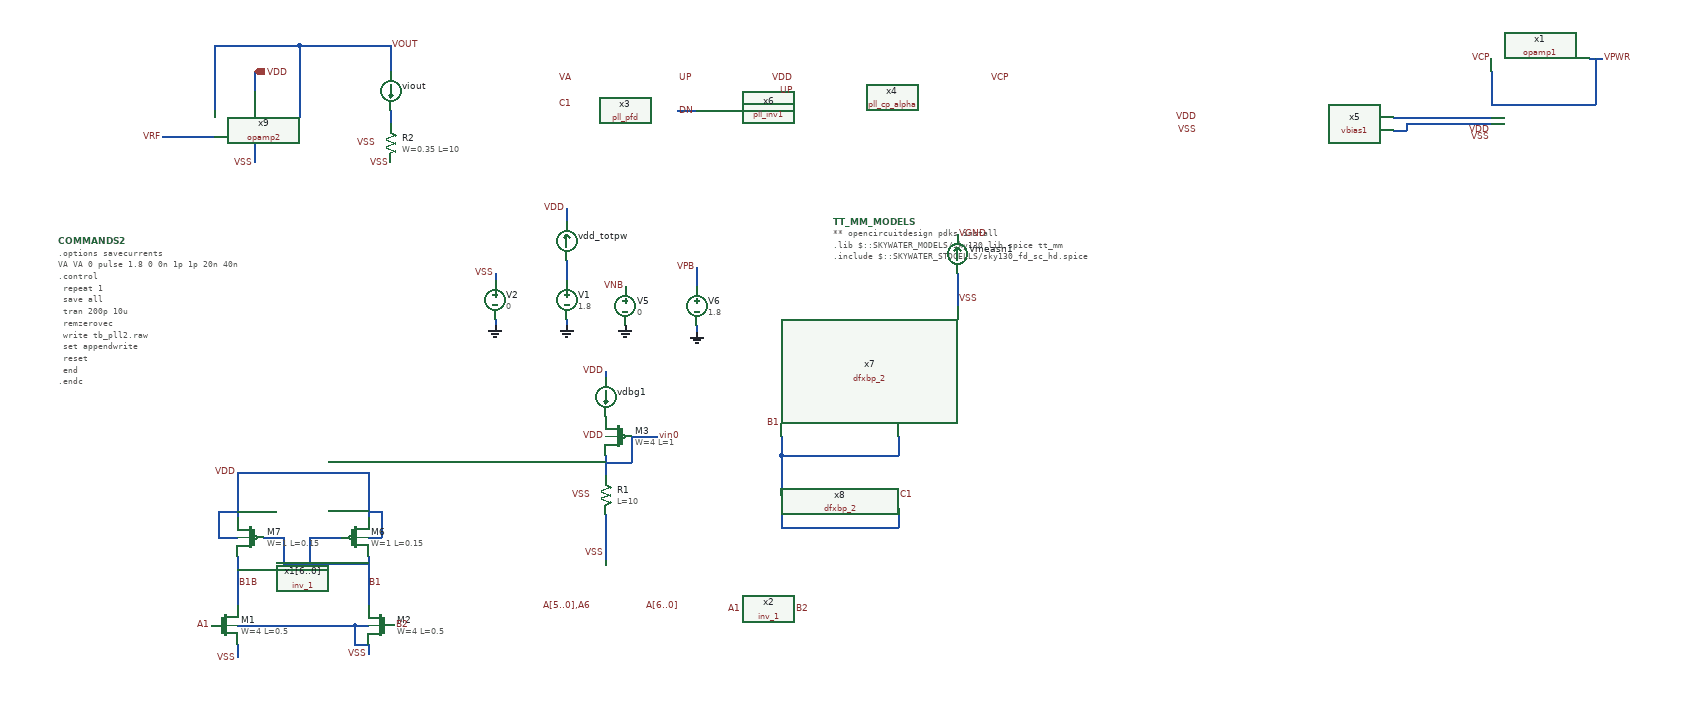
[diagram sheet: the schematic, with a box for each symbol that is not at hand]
v {xschem version=3.4.4 file_version=1.2
}
G {}
K {}
V {}
S {}
E {}
B 2 730 -870 1530 -470 {flags=graph
y1=-0.041
y2=3.9
ypos1=0
ypos2=2
divy=5
subdivy=1
unity=1
x1=8.63019e-06
x2=8.82941e-06
divx=5
subdivx=1
xlabmag=1.0
ylabmag=1.0


dataset=-1
unitx=1
logx=0
logy=0



color="4 5 8 10 10"
node="A1
\\"2 B1 +\\"
\\"2 B1B +\\"
B2
B3"
hilight_wave=0}
B 2 2330 -1270 3130 -870 {flags=graph
y1=-0.013
y2=3.9
ypos1=0
ypos2=2
divy=5
subdivy=1
unity=1
x1=8.63019e-06
x2=8.82941e-06
divx=5
subdivx=1
xlabmag=1.0
ylabmag=1.0


dataset=-1
unitx=1
logx=0
logy=0






color="4 5"
node="\\"UP 2 +\\"
DN"}
B 2 2330 -1670 3130 -1270 {flags=graph
y1=-0.00053
y2=5.9
ypos1=0
ypos2=2
divy=5
subdivy=1
unity=1
x1=8.63019e-06
x2=8.82941e-06
divx=5
subdivx=1
xlabmag=1.0
ylabmag=1.0


dataset=-1
unitx=1
logx=0
logy=0








rainbow=0
color="5 8 7"
node="\\"VA 4 +\\"
\\"C1 2 +\\"
\\"B1\\""}
B 2 1530 -870 2330 -470 {flags=graph
y1=-0.003
y2=0.0032
ypos1=0
ypos2=2
divy=5
subdivy=1
unity=1
x1=8.63019e-06
x2=8.82941e-06
divx=5
subdivx=1
xlabmag=1.0
ylabmag=1.0


dataset=-1
unitx=1
logx=0
logy=0







color=4
node=i(vdd_totpw)}
B 2 2330 -870 3130 -470 {flags=graph
y1=-1.9e-07
y2=1.1
ypos1=0
ypos2=2
divy=5
subdivy=1
unity=1
x1=8.63019e-06
x2=8.82941e-06
divx=5
subdivx=1
xlabmag=1.0
ylabmag=1.0


dataset=-1
unitx=1
logx=0
logy=0






color="18 8"
node="VPWR
VCP"}
N 1740 -1480 1740 -1470 {
lab=VPB}
N 1740 -1410 1740 -1400 {
lab=GND}
N 1740 -1500 1740 -1480 {
lab=VPB}
N 1430 -1490 1430 -1480 {
lab=VSS}
N 1540 -1490 1540 -1480 {
lab=#net1}
N 1430 -1420 1430 -1410 {
lab=GND}
N 1540 -1420 1540 -1410 {
lab=GND}
N 1600 -1340 1600 -1330 {
lab=VDD}
N 1600 -1060 1600 -1050 {
lab=VSS}
N 1600 -1120 1600 -1060 {
lab=VSS}
N 1540 -1590 1540 -1570 {
lab=VDD}
N 1540 -1510 1540 -1490 {
lab=#net1}
N 1600 -1210 1600 -1180 {
lab=vin0}
N 2140 -1490 2140 -1440 {
lab=VSS}
N 1640 -1240 1680 -1240 {
lab=vin0}
N 1640 -1240 1640 -1200 {
lab=vin0}
N 1600 -1200 1640 -1200 {
lab=vin0}
N 3110 -1820 3130 -1820 {
lab=VPWR}
N 2810 -1730 2960 -1730 {
lab=#net2}
N 2830 -1720 2960 -1720 {
lab=#net3}
N 2830 -1720 2830 -1710 {
lab=#net3}
N 2810 -1710 2830 -1710 {
lab=#net3}
N 3120 -1820 3120 -1750 {
lab=VPWR}
N 2960 -1750 3120 -1750 {
lab=VPWR}
N 2960 -1800 2960 -1750 {
lab=VPWR}
N 1710 -1740 1740 -1740 {
lab=DN}
N 1810 -1740 1870 -1750 {
lab=#net4}
N 1870 -1750 1890 -1750 {
lab=#net4}
N 2050 -1240 2050 -1210 {
lab=#net5}
N 1870 -1210 2050 -1210 {
lab=#net5}
N 1870 -1240 1870 -1210 {
lab=#net5}
N 2050 -1130 2050 -1100 {
lab=#net6}
N 1870 -1100 2050 -1100 {
lab=#net6}
N 1870 -1130 1870 -1100 {
lab=#net6}
N 1870 -1210 1870 -1150 {
lab=#net5}
N 1145 -1085 1145 -1035 {
lab=B1B}
N 1165 -1085 1195 -1085 {
lab=B1B}
N 1075 -1085 1105 -1085 {
lab=B1}
N 1105 -1085 1105 -1045 {
lab=B1}
N 1105 -1045 1235 -1045 {
lab=B1}
N 1145 -1085 1165 -1085 {
lab=B1B}
N 1035 -1035 1145 -1035 {
lab=B1B}
N 1235 -1185 1235 -1115 {
lab=VDD}
N 1035 -1185 1035 -1115 {
lab=VDD}
N 1005 -1085 1035 -1085 {
lab=VDD}
N 1005 -1125 1005 -1085 {
lab=VDD}
N 1005 -1125 1035 -1125 {
lab=VDD}
N 1235 -1085 1255 -1085 {
lab=VDD}
N 1255 -1125 1255 -1085 {
lab=VDD}
N 1235 -1125 1255 -1125 {
lab=VDD}
N 1235 -1055 1235 -980 {
lab=B1}
N 1035 -1185 1235 -1185 {
lab=VDD}
N 1235 -920 1235 -905 {
lab=VSS}
N 1215 -920 1235 -920 {
lab=VSS}
N 1215 -950 1215 -920 {
lab=VSS}
N 1215 -950 1235 -950 {
lab=VSS}
N 1035 -920 1035 -900 {
lab=VSS}
N 1035 -950 1215 -950 {
lab=VSS}
N 1035 -1055 1035 -980 {
lab=B1B}
N 1270 -1840 1270 -1800 {
lab=VOUT}
N 1060 -1800 1060 -1770 {
lab=VDD}
N 1060 -1690 1060 -1660 {
lab=VSS}
N 1130 -1840 1130 -1730 {
lab=VOUT}
N 1000 -1840 1130 -1840 {
lab=VOUT}
N 1000 -1840 1000 -1740 {
lab=VOUT}
N 920 -1700 1000 -1700 {
lab=VRF}
N 1130 -1840 1270 -1840 {
lab=VOUT}
N 1270 -1740 1270 -1720 {
lab=#net7}
C {devices/code.sym} 1950 -1570 0 0 {name=TT_MM_MODELS
only_toplevel=true
format="tcleval( @value )"
value="
** opencircuitdesign pdks install
.lib $::SKYWATER_MODELS/sky130.lib.spice tt_mm
.include $::SKYWATER_STDCELLS/sky130_fd_sc_hd.spice                                                              
                        
"
spice_ignore=false}
C {devices/launcher.sym} 2200 -1410 0 0 {name=h17 
descr="Load waves" 
tclcommand="
xschem raw_read $netlist_dir/[file tail [file rootname [xschem get current_name]]].raw tran

"
}
C {devices/simulator_commands_shown.sym} 760 -1540 0 0 {name=COMMANDS2
simulator=ngspice
only_toplevel=false 
value="
.options savecurrents 
VA VA 0 pulse 1.8 0 0n 1p 1p 20n 40n
.control
  repeat 1
    save all
    tran 200p 10u
    remzerovec
    write tb_pll2.raw
    set appendwrite
    reset
    end
.endc
"}
C {devices/vsource.sym} 1630 -1440 0 0 {name=V5 value=0 savecurrent=false}
C {devices/gnd.sym} 1630 -1410 0 0 {name=l5 lab=GND}
C {devices/lab_pin.sym} 1630 -1470 2 1 {name=p6 sig_type=std_logic lab=VNB

}
C {devices/vsource.sym} 1740 -1440 0 0 {name=V6 value=1.8 savecurrent=false}
C {devices/gnd.sym} 1740 -1400 0 0 {name=l6 lab=GND}
C {devices/lab_pin.sym} 1740 -1500 2 1 {name=p14 sig_type=std_logic lab=VPB

}
C {devices/vsource.sym} 1540 -1450 0 0 {name=V1 value=1.8 savecurrent=false}
C {devices/gnd.sym} 1540 -1410 0 0 {name=l2 lab=GND}
C {devices/lab_pin.sym} 1540 -1590 2 1 {name=p19 sig_type=std_logic lab=VDD
}
C {devices/vsource.sym} 1430 -1450 0 0 {name=V2 value=0 savecurrent=false}
C {devices/gnd.sym} 1430 -1410 0 0 {name=l3 lab=GND}
C {devices/lab_pin.sym} 1430 -1490 2 1 {name=p28 sig_type=std_logic lab=VSS
}
C {devices/lab_pin.sym} 1600 -1340 2 1 {name=p2 sig_type=std_logic lab=VDD
}
C {sky130_fd_pr/pfet_01v8_lvt.sym} 1620 -1240 0 1 {name=M3
W=4
L=1
nf=1
mult=1
ad="'int((nf+1)/2) * W/nf * 0.29'" 
pd="'2*int((nf+1)/2) * (W/nf + 0.29)'"
as="'int((nf+2)/2) * W/nf * 0.29'" 
ps="'2*int((nf+2)/2) * (W/nf + 0.29)'"
nrd="'0.29 / W'" nrs="'0.29 / W'"
sa=0 sb=0 sd=0
model=pfet_01v8_lvt
spiceprefix=X
}
C {devices/lab_pin.sym} 1680 -1240 2 0 {name=p5 sig_type=std_logic lab=vin0
}
C {sky130_fd_pr/res_high_po_0p35.sym} 1600 -1150 0 0 {name=R1
L=10
model=res_high_po_0p35
spiceprefix=X
mult=1}
C {devices/ammeter.sym} 1600 -1300 0 0 {name=vdbg1 savecurrent=true}
C {devices/lab_pin.sym} 1580 -1150 2 1 {name=p43 sig_type=std_logic lab=VSS
}
C {devices/lab_pin.sym} 1600 -1240 2 1 {name=p44 sig_type=std_logic lab=VDD
}
C {devices/ammeter.sym} 1540 -1540 2 1 {name=vdd_totpw savecurrent=true}
C {devices/lab_pin.sym} 1600 -1060 2 1 {name=p3 sig_type=std_logic lab=VSS
}
C {sky130_stdcells/inv_1.sym} 1620 -980 0 0 {name=x1[6..0] VGND=VGND VNB=VGND VPB=VDD VPWR=VPWR prefix=sky130_fd_sc_hd__ }
C {devices/lab_pin.sym} 1660 -980 0 1 {name=p7 sig_type=std_logic lab=A[6..0]}
C {devices/lab_pin.sym} 1580 -980 0 0 {name=p9 sig_type=std_logic lab=A[5..0],A6}
C {devices/ammeter.sym} 2140 -1520 2 1 {name=Vmeasn1 savecurrent=true}
C {devices/lab_pin.sym} 2140 -1550 2 0 {name=p12 sig_type=std_logic lab=VGND
}
C {devices/lab_pin.sym} 2140 -1450 2 0 {name=p26 sig_type=std_logic lab=VSS
}
C {sky130_stdcells/inv_1.sym} 1850 -975 0 0 {name=x2 VGND=VGND VNB=VGND VPB=VDD VPWR=VPWR prefix=sky130_fd_sc_hd__ }
C {devices/lab_pin.sym} 1810 -975 2 1 {name=p29 sig_type=std_logic lab=A1
}
C {devices/lab_pin.sym} 1890 -975 0 1 {name=p30 sig_type=std_logic lab=B2
}
C {pll_pfd.sym} 1630 -1740 0 0 {name=x3 VSS=VSS VNB=VSS VPB=VDD VDD=VDD}
C {devices/lab_pin.sym} 1550 -1790 2 1 {name=p25 sig_type=std_logic lab=VA
}
C {devices/lab_pin.sym} 1890 -1790 0 0 {name=p32 sig_type=std_logic lab=VDD}
C {devices/lab_pin.sym} 1890 -1730 0 0 {name=p33 sig_type=std_logic lab=VSS}
C {devices/lab_pin.sym} 1710 -1740 0 1 {name=p11 sig_type=std_logic lab=DN}
C {devices/lab_pin.sym} 1710 -1790 0 1 {name=p8 sig_type=std_logic lab=UP}
C {devices/lab_pin.sym} 1550 -1750 0 0 {name=p31 sig_type=std_logic lab=C1
}
C {devices/lab_pin.sym} 3130 -1820 2 0 {name=p10 sig_type=std_logic lab=VPWR
}
C {opamp1.sym} 3030 -1810 0 0 {name=x1}
C {vbias1.sym} 2660 -1720 0 0 {name=x5}
C {devices/lab_pin.sym} 2510 -1730 0 0 {name=p4 sig_type=std_logic lab=VDD}
C {devices/lab_pin.sym} 2510 -1710 0 0 {name=p13 sig_type=std_logic lab=VSS}
C {devices/lab_pin.sym} 2960 -1710 0 0 {name=p15 sig_type=std_logic lab=VDD}
C {devices/lab_pin.sym} 2960 -1700 0 0 {name=p16 sig_type=std_logic lab=VSS}
C {devices/lab_pin.sym} 2190 -1790 2 0 {name=p17 sig_type=std_logic lab=VCP
}
C {devices/lab_pin.sym} 2960 -1820 2 1 {name=p18 sig_type=std_logic lab=VCP
}
C {pll_cp_alpha.sym} 2040 -1760 0 0 {name=x4}
C {pll_inv1.sym} 1790 -1740 0 0 {name=x6 VSS=VSS VNB=VNB VPB=VPB VDD=VDD}
C {devices/lab_pin.sym} 1890 -1770 0 0 {name=p1 sig_type=std_logic lab=UP}
C {sky130_stdcells/dfxbp_2.sym} 1960 -1250 0 0 {name=x7 VGND=VGND VNB=VNB VPB=VPB VPWR=VPWR prefix=sky130_fd_sc_hd__ }
C {devices/lab_pin.sym} 1870 -1260 0 0 {name=p20 sig_type=std_logic lab=B1
}
C {sky130_stdcells/dfxbp_2.sym} 1960 -1140 0 0 {name=x8 VGND=VGND VNB=VNB VPB=VPB VPWR=VPWR prefix=sky130_fd_sc_hd__ }
C {devices/lab_pin.sym} 2050 -1150 0 1 {name=p23 sig_type=std_logic lab=C1
}
C {sky130_fd_pr/pfet_01v8.sym} 1215 -1085 0 0 {name=M6
L=0.15
W=1
nf=1
mult=1
ad="'int((nf+1)/2) * W/nf * 0.29'" 
pd="'2*int((nf+1)/2) * (W/nf + 0.29)'"
as="'int((nf+2)/2) * W/nf * 0.29'" 
ps="'2*int((nf+2)/2) * (W/nf + 0.29)'"
nrd="'0.29 / W'" nrs="'0.29 / W'"
sa=0 sb=0 sd=0
model=pfet_01v8
spiceprefix=X
}
C {sky130_fd_pr/pfet_01v8.sym} 1055 -1085 0 1 {name=M7
L=0.15
W=1
nf=1
mult=1
ad="'int((nf+1)/2) * W/nf * 0.29'" 
pd="'2*int((nf+1)/2) * (W/nf + 0.29)'"
as="'int((nf+2)/2) * W/nf * 0.29'" 
ps="'2*int((nf+2)/2) * (W/nf + 0.29)'"
nrd="'0.29 / W'" nrs="'0.29 / W'"
sa=0 sb=0 sd=0
model=pfet_01v8
spiceprefix=X
}
C {devices/lab_pin.sym} 1035 -1185 2 1 {name=p24 sig_type=std_logic lab=VDD
}
C {sky130_fd_pr/nfet_03v3_nvt.sym} 1015 -950 0 0 {name=M1
L=0.5
W=4
nf=1
mult=1
ad="'int((nf+1)/2) * W/nf * 0.29'" 
pd="'2*int((nf+1)/2) * (W/nf + 0.29)'"
as="'int((nf+2)/2) * W/nf * 0.29'" 
ps="'2*int((nf+2)/2) * (W/nf + 0.29)'"
nrd="'0.29 / W'" nrs="'0.29 / W'"
sa=0 sb=0 sd=0
model=nfet_03v3_nvt
spiceprefix=X
}
C {sky130_fd_pr/nfet_03v3_nvt.sym} 1255 -950 0 1 {name=M2
L=0.5
W=4
nf=1
mult=1
ad="'int((nf+1)/2) * W/nf * 0.29'" 
pd="'2*int((nf+1)/2) * (W/nf + 0.29)'"
as="'int((nf+2)/2) * W/nf * 0.29'" 
ps="'2*int((nf+2)/2) * (W/nf + 0.29)'"
nrd="'0.29 / W'" nrs="'0.29 / W'"
sa=0 sb=0 sd=0
model=nfet_03v3_nvt
spiceprefix=X
}
C {devices/lab_pin.sym} 1035 -900 2 1 {name=p27 sig_type=std_logic lab=VSS
}
C {devices/lab_pin.sym} 1235 -905 2 1 {name=p34 sig_type=std_logic lab=VSS
}
C {devices/lab_pin.sym} 1275 -950 0 1 {name=p21 sig_type=std_logic lab=B2
}
C {devices/lab_pin.sym} 995 -950 2 1 {name=p22 sig_type=std_logic lab=A1
}
C {devices/lab_pin.sym} 1235 -1015 0 1 {name=p35 sig_type=std_logic lab=B1
}
C {devices/lab_pin.sym} 1035 -1015 0 1 {name=p36 sig_type=std_logic lab=B1B
}
C {devices/lab_pin.sym} 1270 -1840 0 1 {name=p37 sig_type=std_logic lab=VOUT}
C {sky130_fd_pr/res_high_po.sym} 1270 -1690 0 0 {name=R2
W=0.35
L=10
model=res_high_po
spiceprefix=X
mult=1}
C {devices/lab_pin.sym} 1270 -1660 0 0 {name=p38 sig_type=std_logic lab=VSS}
C {opamp2.sym} 1060 -1730 0 0 {name=x9}
C {devices/lab_pin.sym} 1060 -1660 0 0 {name=p39 sig_type=std_logic lab=VSS}
C {devices/iopin.sym} 1060 -1800 0 1 { name=p40 lab=VDD }
C {devices/lab_pin.sym} 920 -1700 0 0 {name=p41 sig_type=std_logic lab=VRF}
C {devices/lab_pin.sym} 1250 -1690 0 0 {name=p42 sig_type=std_logic lab=VSS}
C {devices/ammeter.sym} 1270 -1770 0 0 {name=viout savecurrent=true}
